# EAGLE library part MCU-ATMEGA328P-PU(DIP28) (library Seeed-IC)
310010051

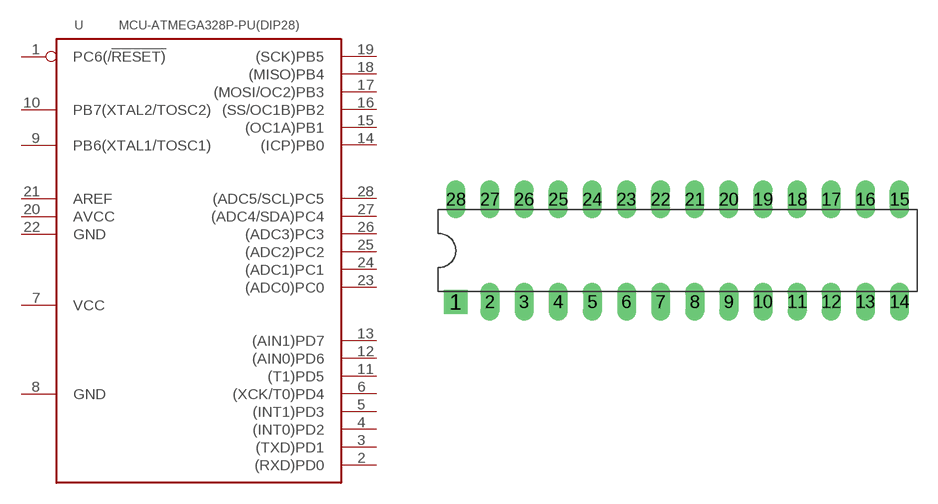
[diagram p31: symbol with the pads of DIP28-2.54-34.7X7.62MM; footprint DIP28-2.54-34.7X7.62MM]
Designator prefix U

## MCU-ATMEGA328P-PU(DIP28) (MPN: ATMEGA328P-PU)  [DIP28-2.54-34.7X7.62MM]
1  PC6(/!RESET)
2  (RXD)PD0
3  (TXD)PD1
4  (INT0)PD2
5  (INT1)PD3
6  (XCK/T0)PD4
7  VCC
8  GND
9  PB6(XTAL1/TOSC1)
10  PB7(XTAL2/TOSC2)
11  (T1)PD5
12  (AIN0)PD6
13  (AIN1)PD7
14  (ICP)PB0
15  (OC1A)PB1
16  (SS/OC1B)PB2
17  (MOSI/OC2)PB3
18  (MISO)PB4
19  (SCK)PB5
20  AVCC
21  AREF
22  GND
23  (ADC0)PC0
24  (ADC1)PC1
25  (ADC2)PC2
26  (ADC3)PC3
27  (ADC4/SDA)PC4
28  (ADC5/SCL)PC5

## Footprint DIP28-2.54-34.7X7.62MM (pad centres in mm)
drill 0.9 pad 1.778 square: 1 -16.51,-3.81
drill 0.9 pad 1.4 long: 2 -13.97,-3.81; 3 -11.43,-3.81; 4 -8.89,-3.81; 5 -6.35,-3.81; 6 -3.81,-3.81; 7 -1.27,-3.81; 8 1.27,-3.81; 9 3.81,-3.81; 10 6.35,-3.81; 11 8.89,-3.81; 12 11.43,-3.81; 13 13.97,-3.81; 14 16.51,-3.81; 15 16.51,3.81; 16 13.97,3.81; 17 11.43,3.81; 18 8.89,3.81; 19 6.35,3.81; 20 3.81,3.81; 21 1.27,3.81; 22 -1.27,3.81; 23 -3.81,3.81; 24 -6.35,3.81; 25 -8.89,3.81; 26 -11.43,3.81; 27 -13.97,3.81; 28 -16.51,3.81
